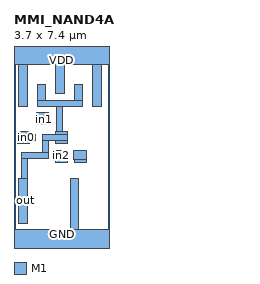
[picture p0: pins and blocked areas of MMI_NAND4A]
MACRO MMI_NAND4A
	CLASS CORE ;
	FOREIGN MMI_NAND4A 0 0 ;
	SIZE 3.7 BY 7.4 ;
	SYMMETRY X Y ;
	SITE CORE1 ;
	PIN out
		DIRECTION output ;
		USE SIGNAL ;
		PORT
			LAYER M1 ;
			RECT 0.9 5.52 1.24 6.13 ;
			LAYER M1 ;
			RECT 2.34 5.52 2.68 6.13 ;
			LAYER M1 ;
			RECT 0.9 5.29 2.68 5.52 ;
			LAYER M1 ;
			RECT 1.66 4.295 1.89 5.29 ;
			LAYER M1 ;
			RECT 1.625 4.185 2.075 4.295 ;
			LAYER M1 ;
			RECT 1.11 3.955 2.075 4.185 ;
			LAYER M1 ;
			RECT 1.11 3.495 1.34 3.955 ;
			LAYER M1 ;
			RECT 1.625 3.845 2.075 3.955 ;
			LAYER M1 ;
			RECT 0.29 3.265 1.34 3.495 ;
			LAYER M1 ;
			RECT 0.29 2.49 0.52 3.265 ;
			LAYER M1 ;
			RECT 0.18 0.73 0.52 2.49 ;
		END
		AntennaDiffArea 1.8768 ;
	END out
	PIN in1
		DIRECTION input ;
		USE SIGNAL ;
		PORT
			LAYER M1 ;
			RECT 0.885 4.93 1.335 5.035 ;
			LAYER M1 ;
			RECT 0.885 4.59 1.43 4.93 ;
			LAYER M1 ;
			RECT 0.885 4.585 1.335 4.59 ;
		END
		AntennaGateArea 0.4968 ;
	END in1
	PIN GND
		DIRECTION inout ;
		USE GROUND ;
		PORT
			LAYER M1 ;
			RECT 2.19 0.5 2.53 2.49 ;
			LAYER M1 ;
			RECT 0 -0.5 3.7 0.5 ;
		END
	END GND
	PIN in2
		DIRECTION input ;
		USE SIGNAL ;
		PORT
			LAYER M1 ;
			RECT 1.625 3.55 2.075 3.555 ;
			LAYER M1 ;
			RECT 1.57 3.21 2.075 3.55 ;
			LAYER M1 ;
			RECT 1.625 3.105 2.075 3.21 ;
		END
		AntennaGateArea 0.4968 ;
	END in2
	PIN VDD
		DIRECTION inout ;
		USE POWER ;
		PORT
			LAYER M1 ;
			RECT 0 6.9 3.7 7.9 ;
			LAYER M1 ;
			RECT 0.18 5.29 0.52 6.9 ;
			LAYER M1 ;
			RECT 1.62 5.79 1.96 6.9 ;
			LAYER M1 ;
			RECT 3.06 5.29 3.4 6.9 ;
		END
	END VDD
	PIN in3
		DIRECTION input ;
		USE SIGNAL ;
		PORT
			LAYER M1 ;
			RECT 2.365 3.55 2.815 3.555 ;
			LAYER M1 ;
			RECT 2.305 3.21 2.815 3.55 ;
			LAYER M1 ;
			RECT 2.365 3.105 2.815 3.21 ;
		END
		AntennaGateArea 0.4968 ;
	END in3
	PIN in0
		DIRECTION input ;
		USE SIGNAL ;
		PORT
			LAYER M1 ;
			RECT 0.145 4.24 0.595 4.295 ;
			LAYER M1 ;
			RECT 0.145 4.185 0.76 4.24 ;
			LAYER M1 ;
			RECT 0.145 3.955 0.825 4.185 ;
			LAYER M1 ;
			RECT 0.145 3.9 0.76 3.955 ;
			LAYER M1 ;
			RECT 0.145 3.845 0.595 3.9 ;
		END
		AntennaGateArea 0.4968 ;
	END in0
	OBS
	END
END MMI_NAND4A
